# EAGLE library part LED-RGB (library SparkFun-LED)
LED-RGB 6 pin RGB LED (no common connector) Packages: PLCC-6 LED-TRICOLOR-5050 - No built-in IC SparkFun Products: Digital Sandbox LED- SMD RGB

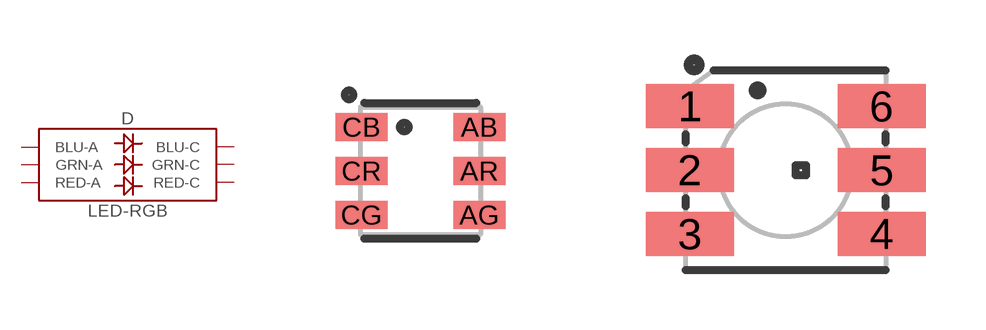
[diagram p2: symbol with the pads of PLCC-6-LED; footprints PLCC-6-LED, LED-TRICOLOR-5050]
Designator prefix D

## LED-RGBPLCC-6 (PROD_ID: DIO-12113; VALUE: RGB)  [PLCC-6-LED]
AB  BLU-A
AG  GRN-A
AR  RED-A
CB  BLU-C
CG  GRN-C
CR  RED-C

## LED-RGBNO_IC (PROD_ID: DIO-10298)  [LED-TRICOLOR-5050]
1  GRN-A
2  RED-A
3  BLU-A
4  BLU-C
5  RED-C
6  GRN-C

## LED-RGBBRG (PROD_ID: DIO-16048)  [LED-TRICOLOR-5050]
1  BLU-C
2  RED-C
3  GRN-C
4  GRN-A
5  RED-A
6  BLU-A

## Footprint PLCC-6-LED (pad centres in mm)
PLCC-6-LED Specifications: Pin count: 6 Size: 3.2*2.8*1.39mm Datasheet referenced for footprint: LTRB GFSF Example device: RGB-LED-PLCC
smd 1.3 x 0.7: AB 1.475,1.1; AG 1.475,-1.1; AR 1.475,0; CB -1.475,1.1; CG -1.475,-1.1; CR -1.475,0

## Footprint LED-TRICOLOR-5050 (pad centres in mm)
5050 SMD RGB LED Specifications: Pin count: 6 Pin pitch: 0.6mm Area: 5.0mm x 5.mm Thickness: 2.6mm Datasheet referenced for footprint: 5060BRG4 Example device(s): LED-RGB
smd 2.2 x 1.1: 1 -2.4,1.6; 2 -2.4,0; 3 -2.4,-1.6; 4 2.4,-1.6; 5 2.4,0; 6 2.4,1.6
